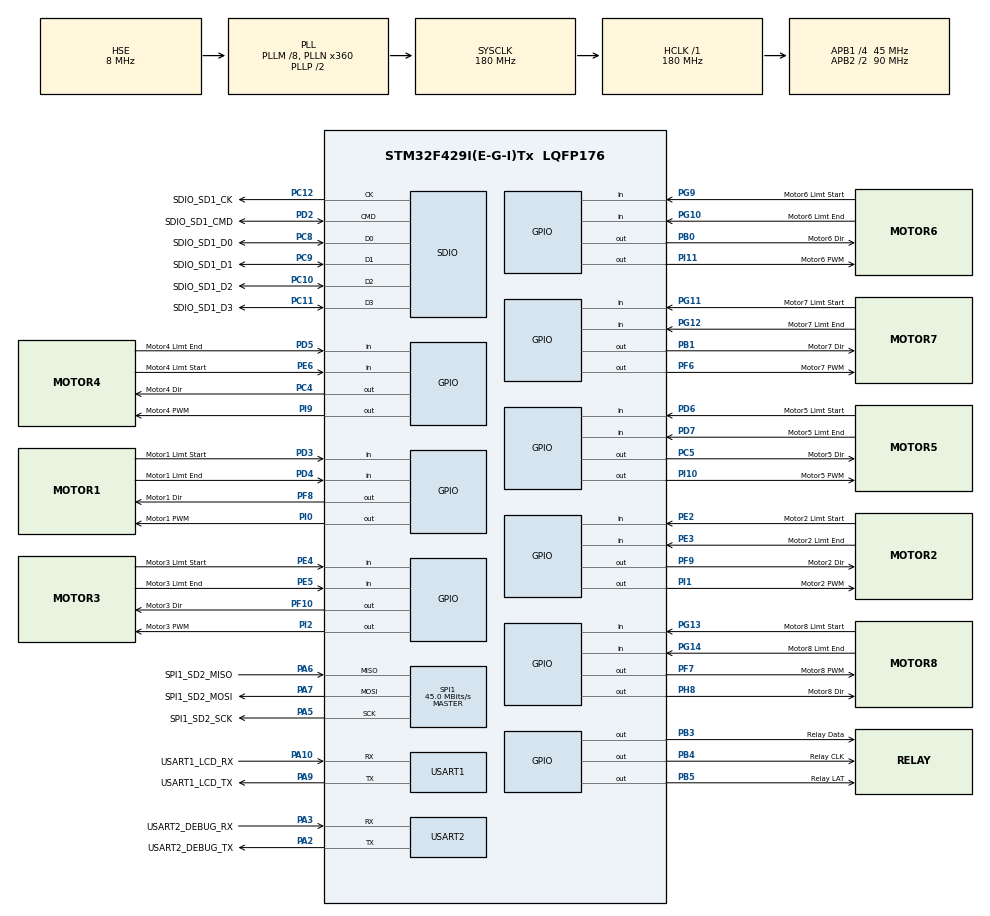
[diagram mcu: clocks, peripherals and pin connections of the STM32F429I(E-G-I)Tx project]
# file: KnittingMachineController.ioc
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Dma.Request0=SDIO_RX
Dma.Request1=SDIO_TX
Dma.SDIO_RX.0.Direction=DMA_PERIPH_TO_MEMORY
Dma.SDIO_RX.0.FIFOMode=DMA_FIFOMODE_ENABLE
Dma.SDIO_RX.0.FIFOThreshold=DMA_FIFO_THRESHOLD_FULL
Dma.SDIO_RX.0.Instance=DMA2_Stream3
Dma.SDIO_RX.0.MemBurst=DMA_MBURST_INC4
Dma.SDIO_RX.0.MemDataAlignment=DMA_MDATAALIGN_WORD
Dma.SDIO_RX.0.MemInc=DMA_MINC_ENABLE
Dma.SDIO_RX.0.Mode=DMA_PFCTRL
Dma.SDIO_RX.0.PeriphBurst=DMA_PBURST_INC4
Dma.SDIO_RX.0.PeriphDataAlignment=DMA_PDATAALIGN_WORD
Dma.SDIO_RX.0.PeriphInc=DMA_PINC_DISABLE
Dma.SDIO_RX.0.Priority=DMA_PRIORITY_LOW
Dma.SDIO_TX.1.Direction=DMA_MEMORY_TO_PERIPH
Dma.SDIO_TX.1.FIFOMode=DMA_FIFOMODE_ENABLE
Dma.SDIO_TX.1.FIFOThreshold=DMA_FIFO_THRESHOLD_FULL
Dma.SDIO_TX.1.Instance=DMA2_Stream6
Dma.SDIO_TX.1.MemBurst=DMA_MBURST_INC4
Dma.SDIO_TX.1.MemDataAlignment=DMA_MDATAALIGN_WORD
Dma.SDIO_TX.1.MemInc=DMA_MINC_ENABLE
Dma.SDIO_TX.1.Mode=DMA_PFCTRL
Dma.SDIO_TX.1.PeriphBurst=DMA_PBURST_INC4
Dma.SDIO_TX.1.PeriphDataAlignment=DMA_PDATAALIGN_WORD
Dma.SDIO_TX.1.PeriphInc=DMA_PINC_DISABLE
Dma.SDIO_TX.1.Priority=DMA_PRIORITY_LOW
Mcu.Family=STM32F4
Mcu.Name=STM32F429I(E-G-I)Tx
Mcu.Package=LQFP176
NVIC.DMA2_Stream3_IRQn=true\:6\:0\:true\:false\:true
NVIC.DMA2_Stream6_IRQn=true\:6\:0\:true\:false\:true
NVIC.PriorityGroup=NVIC_PRIORITYGROUP_4
NVIC.SDIO_IRQn=true\:5\:0\:true\:false\:true
NVIC.TIM1_UP_TIM10_IRQn=true\:0\:0\:false\:false\:true
NVIC.TIM2_IRQn=true\:0\:0\:false\:false\:true
NVIC.TIM3_IRQn=true\:0\:0\:false\:false\:true
NVIC.TIM4_IRQn=true\:0\:0\:false\:false\:true
NVIC.TIM5_IRQn=true\:0\:0\:false\:false\:true
NVIC.TIM6_DAC_IRQn=true\:0\:0\:true\:false\:true
NVIC.TIM7_IRQn=true\:0\:0\:true\:false\:true
NVIC.TIM8_UP_TIM13_IRQn=true\:0\:0\:false\:false\:true
NVIC.USART1_IRQn=true\:0\:0\:false\:false\:true
PA10.GPIO_Label=USART1_LCD_RX
PA10.Mode=Asynchronous
PA10.Signal=USART1_RX
PA13.Mode=Serial_Wire
PA13.Signal=SYS_JTMS-SWDIO
PA14.Mode=Serial_Wire
PA14.Signal=SYS_JTCK-SWCLK
PA2.GPIO_Label=USART2_DEBUG_TX
PA2.Mode=Asynchronous
PA2.Signal=USART2_TX
PA3.GPIO_Label=USART2_DEBUG_RX
PA3.Mode=Asynchronous
PA3.Signal=USART2_RX
PA5.GPIO_Label=SPI1_SD2_SCK
PA5.Mode=Full_Duplex_Master
PA5.Signal=SPI1_SCK
PA6.GPIO_Label=SPI1_SD2_MISO
PA6.Mode=Full_Duplex_Master
PA6.Signal=SPI1_MISO
PA7.GPIO_Label=SPI1_SD2_MOSI
PA7.Mode=Full_Duplex_Master
PA7.Signal=SPI1_MOSI
PA9.GPIO_Label=USART1_LCD_TX
PA9.Mode=Asynchronous
PA9.Signal=USART1_TX
PB0.GPIO_Label=Motor6 Dir
PB0.GPIO_Speed=GPIO_SPEED_FREQ_VERY_HIGH
PB0.Signal=GPIO_Output
PB1.GPIO_Label=Motor7 Dir
PB1.GPIO_Speed=GPIO_SPEED_FREQ_VERY_HIGH
PB1.Signal=GPIO_Output
PB3.GPIO_Label=Relay Data
PB3.GPIO_Speed=GPIO_SPEED_FREQ_VERY_HIGH
PB3.Signal=GPIO_Output
PB4.GPIO_Label=Relay CLK
PB4.GPIO_Speed=GPIO_SPEED_FREQ_VERY_HIGH
PB4.Signal=GPIO_Output
PB5.GPIO_Label=Relay LAT
PB5.GPIO_Speed=GPIO_SPEED_FREQ_VERY_HIGH
PB5.Signal=GPIO_Output
PC10.GPIO_Label=SDIO_SD1_D2
PC10.Mode=SD_4_bits_Wide_bus
PC10.Signal=SDIO_D2
PC11.GPIO_Label=SDIO_SD1_D3
PC11.Mode=SD_4_bits_Wide_bus
PC11.Signal=SDIO_D3
PC12.GPIO_Label=SDIO_SD1_CK
PC12.Mode=SD_4_bits_Wide_bus
PC12.Signal=SDIO_CK
PC4.GPIO_Label=Motor4 Dir
PC4.GPIO_Speed=GPIO_SPEED_FREQ_VERY_HIGH
PC4.Signal=GPIO_Output
PC5.GPIO_Label=Motor5 Dir
PC5.GPIO_Speed=GPIO_SPEED_FREQ_VERY_HIGH
PC5.Signal=GPIO_Output
PC8.GPIO_Label=SDIO_SD1_D0
PC8.Mode=SD_4_bits_Wide_bus
PC8.Signal=SDIO_D0
PC9.GPIO_Label=SDIO_SD1_D1
PC9.Mode=SD_4_bits_Wide_bus
PC9.Signal=SDIO_D1
PD2.GPIO_Label=SDIO_SD1_CMD
PD2.Mode=SD_4_bits_Wide_bus
PD2.Signal=SDIO_CMD
PD3.GPIO_Label=Motor1 Limt Start
PD3.GPIO_PuPd=GPIO_PULLUP
PD3.Signal=GPIO_Input
PD4.GPIO_Label=Motor1 Limt End
PD4.GPIO_PuPd=GPIO_PULLUP
PD4.Signal=GPIO_Input
PD5.GPIO_Label=Motor4 Limt End
PD5.GPIO_PuPd=GPIO_PULLUP
PD5.Signal=GPIO_Input
PD6.GPIO_Label=Motor5 Limt Start
PD6.GPIO_PuPd=GPIO_PULLUP
PD6.Signal=GPIO_Input
PD7.GPIO_Label=Motor5 Limt End
PD7.GPIO_PuPd=GPIO_PULLUP
PD7.Signal=GPIO_Input
PE2.GPIO_Label=Motor2 Limt Start
PE2.GPIO_PuPd=GPIO_PULLUP
PE2.Signal=GPIO_Input
PE3.GPIO_Label=Motor2 Limt End
PE3.GPIO_PuPd=GPIO_PULLUP
PE3.Signal=GPIO_Input
PE4.GPIO_Label=Motor3 Limt Start
PE4.GPIO_PuPd=GPIO_PULLUP
PE4.Signal=GPIO_Input
PE5.GPIO_Label=Motor3 Limt End
PE5.GPIO_PuPd=GPIO_PULLUP
PE5.Signal=GPIO_Input
PE6.GPIO_Label=Motor4 Limt Start
PE6.GPIO_PuPd=GPIO_PULLUP
PE6.Signal=GPIO_Input
PF10.GPIO_Label=Motor3 Dir
PF10.GPIO_Speed=GPIO_SPEED_FREQ_VERY_HIGH
PF10.Signal=GPIO_Output
PF6.GPIO_Label=Motor7 PWM
PF6.GPIO_Speed=GPIO_SPEED_FREQ_VERY_HIGH
PF6.Signal=GPIO_Output
PF7.GPIO_Label=Motor8 PWM
PF7.GPIO_Speed=GPIO_SPEED_FREQ_VERY_HIGH
PF7.Signal=GPIO_Output
PF8.GPIO_Label=Motor1 Dir
PF8.GPIO_Speed=GPIO_SPEED_FREQ_VERY_HIGH
PF8.Signal=GPIO_Output
PF9.GPIO_Label=Motor2 Dir
PF9.GPIO_Speed=GPIO_SPEED_FREQ_VERY_HIGH
PF9.Signal=GPIO_Output
PG10.GPIO_Label=Motor6 Limt End
PG10.GPIO_PuPd=GPIO_PULLUP
PG10.Signal=GPIO_Input
PG11.GPIO_Label=Motor7 Limt Start
PG11.GPIO_PuPd=GPIO_PULLUP
PG11.Signal=GPIO_Input
PG12.GPIO_Label=Motor7 Limt End
PG12.GPIO_PuPd=GPIO_PULLUP
PG12.Signal=GPIO_Input
PG13.GPIO_Label=Motor8 Limt Start
PG13.GPIO_PuPd=GPIO_PULLUP
PG13.Signal=GPIO_Input
PG14.GPIO_Label=Motor8 Limt End
PG14.GPIO_PuPd=GPIO_PULLUP
PG14.Signal=GPIO_Input
PG9.GPIO_Label=Motor6 Limt Start
PG9.GPIO_PuPd=GPIO_PULLUP
PG9.Signal=GPIO_Input
PH0/OSC_IN.Mode=HSE-External-Oscillator
PH0/OSC_IN.Signal=RCC_OSC_IN
PH1/OSC_OUT.Mode=HSE-External-Oscillator
PH1/OSC_OUT.Signal=RCC_OSC_OUT
PH8.GPIO_Label=Motor8 Dir
PH8.GPIO_Speed=GPIO_SPEED_FREQ_VERY_HIGH
PH8.Signal=GPIO_Output
PI0.GPIO_Label=Motor1 PWM
PI0.GPIO_Speed=GPIO_SPEED_FREQ_VERY_HIGH
PI0.Signal=GPIO_Output
PI1.GPIO_Label=Motor2 PWM
PI1.GPIO_Speed=GPIO_SPEED_FREQ_VERY_HIGH
PI1.Signal=GPIO_Output
PI10.GPIO_Label=Motor5 PWM
PI10.GPIO_Speed=GPIO_SPEED_FREQ_VERY_HIGH
PI10.Signal=GPIO_Output
PI11.GPIO_Label=Motor6 PWM
PI11.GPIO_Speed=GPIO_SPEED_FREQ_VERY_HIGH
PI11.Signal=GPIO_Output
PI2.GPIO_Label=Motor3 PWM
PI2.GPIO_Speed=GPIO_SPEED_FREQ_VERY_HIGH
PI2.Signal=GPIO_Output
PI9.GPIO_Label=Motor4 PWM
PI9.GPIO_Speed=GPIO_SPEED_FREQ_VERY_HIGH
PI9.Signal=GPIO_Output
ProjectManager.HeapSize=0x200
ProjectManager.StackSize=0x400
ProjectManager.TargetToolchain=MDK-ARM V5
RCC.48MHZClocksFreq_Value=45000000
RCC.AHBFreq_Value=180000000
RCC.APB1CLKDivider=RCC_HCLK_DIV4
RCC.APB1Freq_Value=45000000
RCC.APB1TimFreq_Value=90000000
RCC.APB2CLKDivider=RCC_HCLK_DIV2
RCC.APB2Freq_Value=90000000
RCC.APB2TimFreq_Value=180000000
RCC.CortexFreq_Value=22500000
RCC.Cortex_Div=SYSTICK_CLKSOURCE_HCLK_DIV8
RCC.HCLKFreq_Value=180000000
RCC.HSE_VALUE=8000000
RCC.HSI_VALUE=16000000
RCC.LSE_VALUE=32768
RCC.PLLM=8
RCC.PLLN=360
RCC.PLLQ=8
RCC.PLLSourceVirtual=RCC_PLLSOURCE_HSE
RCC.SYSCLKFreq_VALUE=180000000
RCC.SYSCLKSource=RCC_SYSCLKSOURCE_PLLCLK
RCC.VCOOutputFreq_Value=360000000
SDIO.BusWide=SDIO_BUS_WIDE_1B
SDIO.WideMode=SDIO_BUS_WIDE_4B
SPI1.BaudRatePrescaler=SPI_BAUDRATEPRESCALER_2
SPI1.CalculateBaudRate=45.0 MBits/s
SPI1.Mode=SPI_MODE_MASTER
TIM1.Period=1
TIM1.Prescaler=5000
TIM2.Period=1
TIM2.Prescaler=2500
TIM3.Period=1
TIM3.Prescaler=2500
TIM4.Period=1
TIM4.Prescaler=2500
TIM5.Period=1
TIM5.Prescaler=2500
TIM6.Period=1
TIM6.Prescaler=2500
TIM7.Period=1
TIM7.Prescaler=2500
TIM8.Period=1
TIM8.Prescaler=5000
VP_CRC_VS_CRC.Mode=CRC_Activate
VP_TIM1_VS_ClockSourceINT.Mode=Internal
VP_TIM2_VS_ClockSourceINT.Mode=Internal
VP_TIM3_VS_ClockSourceINT.Mode=Internal
VP_TIM4_VS_ClockSourceINT.Mode=Internal
VP_TIM5_VS_ClockSourceINT.Mode=Internal
VP_TIM6_VS_ClockSourceINT.Mode=Enable_Timer
VP_TIM7_VS_ClockSourceINT.Mode=Enable_Timer
VP_TIM8_VS_ClockSourceINT.Mode=Internal
board=KnittingMachineController

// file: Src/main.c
/**
  ******************************************************************************
  * File Name          : main.c
  * Description        : Main program body
  ******************************************************************************
  *
  * COPYRIGHT(c) 2016 STMicroelectronics
  *
  * Redistribution and use in source and binary forms, with or without modification,
  * are permitted provided that the following conditions are met:
  *   1. Redistributions of source code must retain the above copyright notice,
  *      this list of conditions and the following disclaimer.
  *   2. Redistributions in binary form must reproduce the above copyright notice,
  *      this list of conditions and the following disclaimer in the documentation
  *      and/or other materials provided with the distribution.
  *   3. Neither the name of STMicroelectronics nor the names of its contributors
  *      may be used to endorse or promote products derived from this software
  *      without specific prior written permission.
  *
  * THIS SOFTWARE IS PROVIDED BY THE COPYRIGHT HOLDERS AND CONTRIBUTORS "AS IS"
  * AND ANY EXPRESS OR IMPLIED WARRANTIES, INCLUDING, BUT NOT LIMITED TO, THE
  * IMPLIED WARRANTIES OF MERCHANTABILITY AND FITNESS FOR A PARTICULAR PURPOSE ARE
  * DISCLAIMED. IN NO EVENT SHALL THE COPYRIGHT HOLDER OR CONTRIBUTORS BE LIABLE
  * FOR ANY DIRECT, INDIRECT, INCIDENTAL, SPECIAL, EXEMPLARY, OR CONSEQUENTIAL
  * DAMAGES (INCLUDING, BUT NOT LIMITED TO, PROCUREMENT OF SUBSTITUTE GOODS OR
  * SERVICES; LOSS OF USE, DATA, OR PROFITS; OR BUSINESS INTERRUPTION) HOWEVER
  * CAUSED AND ON ANY THEORY OF LIABILITY, WHETHER IN CONTRACT, STRICT LIABILITY,
  * OR TORT (INCLUDING NEGLIGENCE OR OTHERWISE) ARISING IN ANY WAY OUT OF THE USE
  * OF THIS SOFTWARE, EVEN IF ADVISED OF THE POSSIBILITY OF SUCH DAMAGE.
  *
  ******************************************************************************
  */
#include "stm32f4xx_hal.h"

/* USER CODE BEGIN Includes */
#include <string.h>
/* USER CODE END Includes */

CRC_HandleTypeDef hcrc;

SD_HandleTypeDef hsd;
HAL_SD_CardInfoTypedef SDCardInfo;
DMA_HandleTypeDef hdma_sdio_rx;
DMA_HandleTypeDef hdma_sdio_tx;

SPI_HandleTypeDef hspi1;

TIM_HandleTypeDef htim1;
TIM_HandleTypeDef htim2;
TIM_HandleTypeDef htim3;
TIM_HandleTypeDef htim4;
TIM_HandleTypeDef htim5;
TIM_HandleTypeDef htim6;
TIM_HandleTypeDef htim7;
TIM_HandleTypeDef htim8;

UART_HandleTypeDef huart1;
UART_HandleTypeDef huart2;

/* USER CODE BEGIN PV */
/* Private variables ---------------------------------------------------------*/
HAL_SD_ErrorTypedef Status;
uint32_t Buffer_Tx[512/4], Buffer_Rx[512/4];
uint32_t i;
/* Buffer used for reception */
uint8_t aRxBuffer[20];
/* USER CODE END PV */

void SystemClock_Config(void);
void Error_Handler(void);
static void MX_GPIO_Init(void);
static void MX_DMA_Init(void);
static void MX_CRC_Init(void);
static void MX_SDIO_SD_Init(void);
static void MX_SPI1_Init(void);
static void MX_TIM1_Init(void);
static void MX_TIM2_Init(void);
static void MX_TIM3_Init(void);
static void MX_TIM4_Init(void);
static void MX_TIM5_Init(void);
static void MX_TIM6_Init(void);
static void MX_TIM7_Init(void);
static void MX_TIM8_Init(void);
static void MX_USART1_UART_Init(void);
static void MX_USART2_UART_Init(void);

/* USER CODE BEGIN PFP */
/* Private function prototypes -----------------------------------------------*/

/* USER CODE END PFP */

/* USER CODE BEGIN 0 */
	//define printf function for UART2
	#ifdef __GNUC__
		/* With GCC/RAISONANCE, small printf (option LD Linker->Libraries->Small printf
			 set to 'Yes') calls __io_putchar() */
		#define PUTCHAR_PROTOTYPE int __io_putchar(int ch)
	#else
		#define PUTCHAR_PROTOTYPE int fputc(int ch, FILE *f)
	#endif /* __GNUC__ */
	/**
		* @brief  Retargets the C library printf function to the USART.
		* @param  None
		* @retval None
		*/
	PUTCHAR_PROTOTYPE
	{
		/* Place your implementation of fputc here */
		/* e.g. write a character to the EVAL_COM1 and Loop until the end of transmission */
		HAL_UART_Transmit(&huart2, (uint8_t *)&ch, 1, 0xFFFF);

		return ch;
	}
/* USER CODE END 0 */

int main(void)
{

  /* MCU Configuration----------------------------------------------------------*/

  /* Reset of all peripherals, Initializes the Flash interface and the Systick. */
  HAL_Init();

  /* Configure the system clock */
  SystemClock_Config();

  /* Initialize all configured peripherals */
  MX_GPIO_Init();
  MX_DMA_Init();
  MX_CRC_Init();
  MX_SDIO_SD_Init();
  MX_SPI1_Init();
  MX_TIM1_Init();
  MX_TIM2_Init();
  MX_TIM3_Init();
  MX_TIM4_Init();
  MX_TIM5_Init();
  MX_TIM6_Init();
  MX_TIM7_Init();
  MX_TIM8_Init();
  MX_USART1_UART_Init();
  MX_USART2_UART_Init();

  /* USER CODE BEGIN 2 */
	HAL_TIM_Base_Start_IT(&htim1);
	HAL_Delay(10);
	HAL_TIM_Base_Start_IT(&htim2);
	HAL_Delay(10);
	HAL_TIM_Base_Start_IT(&htim3);
	HAL_Delay(10);
	HAL_TIM_Base_Start_IT(&htim4);
	HAL_Delay(10);
	HAL_TIM_Base_Start_IT(&htim5);
	HAL_Delay(10);
	HAL_TIM_Base_Start_IT(&htim6);
	HAL_Delay(10);
	HAL_TIM_Base_Start_IT(&htim7);
	HAL_Delay(10);
	HAL_TIM_Base_Start_IT(&htim8);
	HAL_Delay(10);
	HAL_UART_Receive_IT(&huart1, (uint8_t *)aRxBuffer, 10);

	//SD testing
		printf(" Warning: this program may erase all the TF card data. \r\n");

    printf("\r\n Initialize SD card successfully!\r\n\r\n");
    printf(" SD card information! \r\n");
    printf(" CardCapacity  : %llu \r\n",SDCardInfo.CardCapacity );
    printf(" CardBlockSize : %d \r\n",SDCardInfo.CardBlockSize);
    printf(" RCA           : %d \r\n",SDCardInfo.RCA);
    printf(" CardType      : %d \r\n",SDCardInfo.CardType);

    /*------------------- Block Write --------------------------*/
    memset(Buffer_Tx,0x15,sizeof(Buffer_Tx));
    if(HAL_SD_WriteBlocks_DMA(&hsd, Buffer_Tx, 0, 512, 1) == SD_OK)
    {
        Status = HAL_SD_CheckWriteOperation(&hsd, (uint32_t)100000000);
        if (Status == SD_OK)
        {
            printf("\r\n Write block successfully!\r\n");
            for(i=0;i<sizeof(Buffer_Tx)>>2;i++)
            {
                printf("%02x:0x%08x ",i,Buffer_Tx[i]);
            }
            printf("\r\n");
        }
        else
            printf("\r\n Write block fail!\r\n");
    }

    /*------------------- Block Read --------------------------*/
    if(HAL_SD_ReadBlocks_DMA(&hsd, Buffer_Rx, 0, 512, 1) == SD_OK)
    {
        Status = HAL_SD_CheckReadOperation(&hsd, 0xFFFF);
        if (Status == SD_OK)
        {
            printf("\r\n Read block successfully!\r\n");
            for(i=0;i<sizeof(Buffer_Rx)>>2;i++)
            {
                printf("%02x:0x%08x ",i,Buffer_Rx[i]);
            }
            printf("\r\n");
        }
        else
            printf("\r\n Read block fail!\r\n");
    }

    /*------------------- Block Erase -------------------------------*/
    Status = HAL_SD_Erase(&hsd, 0, 512);
    if (Status == SD_OK)
			printf("\r\n Erase block successfully!\r\n");
    else
        printf("\r\n Erase block fail!\r\n");

    /*------------------- Block Read --------------------------*/
    if(HAL_SD_ReadBlocks_DMA(&hsd, Buffer_Rx, 0, 512, 1) == SD_OK)
    {
        Status = HAL_SD_CheckReadOperation(&hsd, 0xFFFF);
        if (Status == SD_OK)
        {
            printf("\r\n Read block successfully!\r\n");
            for(i=0;i<sizeof(Buffer_Rx)>>2;i++)
            {
                printf("%02x:0x%08x ",i,Buffer_Rx[i]);
            }
            printf("\r\n");
        }
        else
            printf("\r\n Read block fail!\r\n");
    }
  /* USER CODE END 2 */

  /* Infinite loop */
  /* USER CODE BEGIN WHILE */
	//HAL_UART_Transmit_IT(&huart1, uart_trans, 2);
	//HAL_UART_Transmit(&huart2, uart_trans, 2, 1000);
	printf("\nwelcome to www.waveshere.com !!!\n");
  while (1)
  {
  /* USER CODE END WHILE */

  /* USER CODE BEGIN 3 */

		//HAL_UART_Transmit_IT(&huart1, uart_trans, 2);
		//HAL_GPIO_TogglePin(GPIOF, Motor8_PWM_Pin);
  }
  /* USER CODE END 3 */

}

/** System Clock Configuration
*/
void SystemClock_Config(void)
{

  RCC_OscInitTypeDef RCC_OscInitStruct;
  RCC_ClkInitTypeDef RCC_ClkInitStruct;

  __HAL_RCC_PWR_CLK_ENABLE();

  __HAL_PWR_VOLTAGESCALING_CONFIG(PWR_REGULATOR_VOLTAGE_SCALE1);

  RCC_OscInitStruct.OscillatorType = RCC_OSCILLATORTYPE_HSE;
  RCC_OscInitStruct.HSEState = RCC_HSE_ON;
  RCC_OscInitStruct.PLL.PLLState = RCC_PLL_ON;
  RCC_OscInitStruct.PLL.PLLSource = RCC_PLLSOURCE_HSE;
  RCC_OscInitStruct.PLL.PLLM = 8;
  RCC_OscInitStruct.PLL.PLLN = 360;
  RCC_OscInitStruct.PLL.PLLP = RCC_PLLP_DIV2;
  RCC_OscInitStruct.PLL.PLLQ = 8;
  if (HAL_RCC_OscConfig(&RCC_OscInitStruct) != HAL_OK)
  {
    Error_Handler();
  }

  if (HAL_PWREx_EnableOverDrive() != HAL_OK)
  {
    Error_Handler();
  }

  RCC_ClkInitStruct.ClockType = RCC_CLOCKTYPE_HCLK|RCC_CLOCKTYPE_SYSCLK
                              |RCC_CLOCKTYPE_PCLK1|RCC_CLOCKTYPE_PCLK2;
  RCC_ClkInitStruct.SYSCLKSource = RCC_SYSCLKSOURCE_PLLCLK;
  RCC_ClkInitStruct.AHBCLKDivider = RCC_SYSCLK_DIV1;
  RCC_ClkInitStruct.APB1CLKDivider = RCC_HCLK_DIV4;
  RCC_ClkInitStruct.APB2CLKDivider = RCC_HCLK_DIV2;
  if (HAL_RCC_ClockConfig(&RCC_ClkInitStruct, FLASH_LATENCY_5) != HAL_OK)
  {
    Error_Handler();
  }

  HAL_SYSTICK_Config(HAL_RCC_GetHCLKFreq()/8000);

  HAL_SYSTICK_CLKSourceConfig(SYSTICK_CLKSOURCE_HCLK_DIV8);

  /* SysTick_IRQn interrupt configuration */
  HAL_NVIC_SetPriority(SysTick_IRQn, 0, 0);
}

/* CRC init function */
static void MX_CRC_Init(void)
{

  hcrc.Instance = CRC;
  if (HAL_CRC_Init(&hcrc) != HAL_OK)
  {
    Error_Handler();
  }

}

/* SDIO init function */
static void MX_SDIO_SD_Init(void)
{

  hsd.Instance = SDIO;
  hsd.Init.ClockEdge = SDIO_CLOCK_EDGE_RISING;
  hsd.Init.ClockBypass = SDIO_CLOCK_BYPASS_DISABLE;
  hsd.Init.ClockPowerSave = SDIO_CLOCK_POWER_SAVE_DISABLE;
  hsd.Init.BusWide = SDIO_BUS_WIDE_1B;
  hsd.Init.HardwareFlowControl = SDIO_HARDWARE_FLOW_CONTROL_DISABLE;
  hsd.Init.ClockDiv = 0;
  if (HAL_SD_Init(&hsd, &SDCardInfo) != SD_OK)
  {
    Error_Handler();
  }

  HAL_SD_WideBusOperation_Config(&hsd, SDIO_BUS_WIDE_4B);

}

/* SPI1 init function */
static void MX_SPI1_Init(void)
{

  hspi1.Instance = SPI1;
  hspi1.Init.Mode = SPI_MODE_MASTER;
  hspi1.Init.Direction = SPI_DIRECTION_2LINES;
  hspi1.Init.DataSize = SPI_DATASIZE_8BIT;
  hspi1.Init.CLKPolarity = SPI_POLARITY_LOW;
  hspi1.Init.CLKPhase = SPI_PHASE_1EDGE;
  hspi1.Init.NSS = SPI_NSS_SOFT;
  hspi1.Init.BaudRatePrescaler = SPI_BAUDRATEPRESCALER_2;
  hspi1.Init.FirstBit = SPI_FIRSTBIT_MSB;
  hspi1.Init.TIMode = SPI_TIMODE_DISABLE;
  hspi1.Init.CRCCalculation = SPI_CRCCALCULATION_DISABLE;
  hspi1.Init.CRCPolynomial = 10;
  if (HAL_SPI_Init(&hspi1) != HAL_OK)
  {
    Error_Handler();
  }

}

/* TIM1 init function */
static void MX_TIM1_Init(void)
{

  TIM_ClockConfigTypeDef sClockSourceConfig;
  TIM_MasterConfigTypeDef sMasterConfig;

  htim1.Instance = TIM1;
  htim1.Init.Prescaler = 5000;
  htim1.Init.CounterMode = TIM_COUNTERMODE_UP;
  htim1.Init.Period = 1;
  htim1.Init.ClockDivision = TIM_CLOCKDIVISION_DIV1;
  htim1.Init.RepetitionCounter = 0;
  if (HAL_TIM_Base_Init(&htim1) != HAL_OK)
  {
    Error_Handler();
  }

  sClockSourceConfig.ClockSource = TIM_CLOCKSOURCE_INTERNAL;
  if (HAL_TIM_ConfigClockSource(&htim1, &sClockSourceConfig) != HAL_OK)
  {
    Error_Handler();
  }

  sMasterConfig.MasterOutputTrigger = TIM_TRGO_RESET;
  sMasterConfig.MasterSlaveMode = TIM_MASTERSLAVEMODE_DISABLE;
  if (HAL_TIMEx_MasterConfigSynchronization(&htim1, &sMasterConfig) != HAL_OK)
  {
    Error_Handler();
  }

}

/* TIM2 init function */
static void MX_TIM2_Init(void)
{

  TIM_ClockConfigTypeDef sClockSourceConfig;
  TIM_MasterConfigTypeDef sMasterConfig;

  htim2.Instance = TIM2;
  htim2.Init.Prescaler = 2500;
  htim2.Init.CounterMode = TIM_COUNTERMODE_UP;
  htim2.Init.Period = 1;
  htim2.Init.ClockDivision = TIM_CLOCKDIVISION_DIV1;
  if (HAL_TIM_Base_Init(&htim2) != HAL_OK)
  {
    Error_Handler();
  }

  sClockSourceConfig.ClockSource = TIM_CLOCKSOURCE_INTERNAL;
  if (HAL_TIM_ConfigClockSource(&htim2, &sClockSourceConfig) != HAL_OK)
  {
    Error_Handler();
  }

  sMasterConfig.MasterOutputTrigger = TIM_TRGO_RESET;
  sMasterConfig.MasterSlaveMode = TIM_MASTERSLAVEMODE_DISABLE;
  if (HAL_TIMEx_MasterConfigSynchronization(&htim2, &sMasterConfig) != HAL_OK)
  {
    Error_Handler();
  }

}

/* TIM3 init function */
static void MX_TIM3_Init(void)
{

  TIM_ClockConfigTypeDef sClockSourceConfig;
  TIM_MasterConfigTypeDef sMasterConfig;

  htim3.Instance = TIM3;
  htim3.Init.Prescaler = 2500;
  htim3.Init.CounterMode = TIM_COUNTERMODE_UP;
  htim3.Init.Period = 1;
  htim3.Init.ClockDivision = TIM_CLOCKDIVISION_DIV1;
  if (HAL_TIM_Base_Init(&htim3) != HAL_OK)
  {
    Error_Handler();
  }

  sClockSourceConfig.ClockSource = TIM_CLOCKSOURCE_INTERNAL;
  if (HAL_TIM_ConfigClockSource(&htim3, &sClockSourceConfig) != HAL_OK)
  {
    Error_Handler();
  }

  sMasterConfig.MasterOutputTrigger = TIM_TRGO_RESET;
  sMasterConfig.MasterSlaveMode = TIM_MASTERSLAVEMODE_DISABLE;
  if (HAL_TIMEx_MasterConfigSynchronization(&htim3, &sMasterConfig) != HAL_OK)
  {
    Error_Handler();
  }

}

/* TIM4 init function */
static void MX_TIM4_Init(void)
{

  TIM_ClockConfigTypeDef sClockSourceConfig;
  TIM_MasterConfigTypeDef sMasterConfig;

  htim4.Instance = TIM4;
  htim4.Init.Prescaler = 2500;
  htim4.Init.CounterMode = TIM_COUNTERMODE_UP;
  htim4.Init.Period = 1;
  htim4.Init.ClockDivision = TIM_CLOCKDIVISION_DIV1;
  if (HAL_TIM_Base_Init(&htim4) != HAL_OK)
  {
    Error_Handler();
  }

  sClockSourceConfig.ClockSource = TIM_CLOCKSOURCE_INTERNAL;
  if (HAL_TIM_ConfigClockSource(&htim4, &sClockSourceConfig) != HAL_OK)
  {
    Error_Handler();
  }

  sMasterConfig.MasterOutputTrigger = TIM_TRGO_RESET;
  sMasterConfig.MasterSlaveMode = TIM_MASTERSLAVEMODE_DISABLE;
  if (HAL_TIMEx_MasterConfigSynchronization(&htim4, &sMasterConfig) != HAL_OK)
  {
    Error_Handler();
  }

}

/* TIM5 init function */
static void MX_TIM5_Init(void)
{

  TIM_ClockConfigTypeDef sClockSourceConfig;
  TIM_MasterConfigTypeDef sMasterConfig;

  htim5.Instance = TIM5;
  htim5.Init.Prescaler = 2500;
  htim5.Init.CounterMode = TIM_COUNTERMODE_UP;
  htim5.Init.Period = 1;
  htim5.Init.ClockDivision = TIM_CLOCKDIVISION_DIV1;
  if (HAL_TIM_Base_Init(&htim5) != HAL_OK)
  {
    Error_Handler();
  }

  sClockSourceConfig.ClockSource = TIM_CLOCKSOURCE_INTERNAL;
  if (HAL_TIM_ConfigClockSource(&htim5, &sClockSourceConfig) != HAL_OK)
  {
    Error_Handler();
  }

  sMasterConfig.MasterOutputTrigger = TIM_TRGO_RESET;
  sMasterConfig.MasterSlaveMode = TIM_MASTERSLAVEMODE_DISABLE;
  if (HAL_TIMEx_MasterConfigSynchronization(&htim5, &sMasterConfig) != HAL_OK)
  {
    Error_Handler();
  }

}

/* TIM6 init function */
static void MX_TIM6_Init(void)
{

  TIM_MasterConfigTypeDef sMasterConfig;

  htim6.Instance = TIM6;
  htim6.Init.Prescaler = 2500;
  htim6.Init.CounterMode = TIM_COUNTERMODE_UP;
  htim6.Init.Period = 1;
  if (HAL_TIM_Base_Init(&htim6) != HAL_OK)
  {
    Error_Handler();
  }

  sMasterConfig.MasterOutputTrigger = TIM_TRGO_RESET;
  sMasterConfig.MasterSlaveMode = TIM_MASTERSLAVEMODE_DISABLE;
  if (HAL_TIMEx_MasterConfigSynchronization(&htim6, &sMasterConfig) != HAL_OK)
  {
    Error_Handler();
  }

}

/* TIM7 init function */
static void MX_TIM7_Init(void)
{

  TIM_MasterConfigTypeDef sMasterConfig;

  htim7.Instance = TIM7;
  htim7.Init.Prescaler = 2500;
  htim7.Init.CounterMode = TIM_COUNTERMODE_UP;
  htim7.Init.Period = 1;
  if (HAL_TIM_Base_Init(&htim7) != HAL_OK)
  {
    Error_Handler();
  }

  sMasterConfig.MasterOutputTrigger = TIM_TRGO_RESET;
  sMasterConfig.MasterSlaveMode = TIM_MASTERSLAVEMODE_DISABLE;
  if (HAL_TIMEx_MasterConfigSynchronization(&htim7, &sMasterConfig) != HAL_OK)
  {
    Error_Handler();
  }

}

/* TIM8 init function */
static void MX_TIM8_Init(void)
{

  TIM_ClockConfigTypeDef sClockSourceConfig;
  TIM_MasterConfigTypeDef sMasterConfig;

  htim8.Instance = TIM8;
  htim8.Init.Prescaler = 5000;
  htim8.Init.CounterMode = TIM_COUNTERMODE_UP;
  htim8.Init.Period = 1;
  htim8.Init.ClockDivision = TIM_CLOCKDIVISION_DIV1;
  htim8.Init.RepetitionCounter = 0;
  if (HAL_TIM_Base_Init(&htim8) != HAL_OK)
  {
    Error_Handler();
  }

  sClockSourceConfig.ClockSource = TIM_CLOCKSOURCE_INTERNAL;
  if (HAL_TIM_ConfigClockSource(&htim8, &sClockSourceConfig) != HAL_OK)
  {
    Error_Handler();
  }

  sMasterConfig.MasterOutputTrigger = TIM_TRGO_RESET;
  sMasterConfig.MasterSlaveMode = TIM_MASTERSLAVEMODE_DISABLE;
  if (HAL_TIMEx_MasterConfigSynchronization(&htim8, &sMasterConfig) != HAL_OK)
  {
    Error_Handler();
  }

}

/* USART1 init function */
static void MX_USART1_UART_Init(void)
{

  huart1.Instance = USART1;
  huart1.Init.BaudRate = 115200;
  huart1.Init.WordLength = UART_WORDLENGTH_8B;
  huart1.Init.StopBits = UART_STOPBITS_1;
  huart1.Init.Parity = UART_PARITY_NONE;
  huart1.Init.Mode = UART_MODE_TX_RX;
  huart1.Init.HwFlowCtl = UART_HWCONTROL_NONE;
  huart1.Init.OverSampling = UART_OVERSAMPLING_16;
  if (HAL_UART_Init(&huart1) != HAL_OK)
  {
    Error_Handler();
  }

}

/* USART2 init function */
static void MX_USART2_UART_Init(void)
{

  huart2.Instance = USART2;
  huart2.Init.BaudRate = 115200;
  huart2.Init.WordLength = UART_WORDLENGTH_8B;
  huart2.Init.StopBits = UART_STOPBITS_1;
  huart2.Init.Parity = UART_PARITY_NONE;
  huart2.Init.Mode = UART_MODE_TX_RX;
  huart2.Init.HwFlowCtl = UART_HWCONTROL_NONE;
  huart2.Init.OverSampling = UART_OVERSAMPLING_16;
  if (HAL_UART_Init(&huart2) != HAL_OK)
  {
    Error_Handler();
  }

}

static void MX_DMA_Init(void)
{
  /* DMA controller clock enable */
  __HAL_RCC_DMA2_CLK_ENABLE();

  /* DMA interrupt init */
  /* DMA2_Stream3_IRQn interrupt configuration */
  HAL_NVIC_SetPriority(DMA2_Stream3_IRQn, 6, 0);
  HAL_NVIC_EnableIRQ(DMA2_Stream3_IRQn);
  /* DMA2_Stream6_IRQn interrupt configuration */
  HAL_NVIC_SetPriority(DMA2_Stream6_IRQn, 6, 0);
  HAL_NVIC_EnableIRQ(DMA2_Stream6_IRQn);

}

/** Configure pins as
        * Analog
        * Input
        * Output
        * EVENT_OUT
        * EXTI
*/
static void MX_GPIO_Init(void)
{

  GPIO_InitTypeDef GPIO_InitStruct;

  /* GPIO Ports Clock Enable */
  __HAL_RCC_GPIOE_CLK_ENABLE();
  __HAL_RCC_GPIOI_CLK_ENABLE();
  __HAL_RCC_GPIOF_CLK_ENABLE();
  __HAL_RCC_GPIOH_CLK_ENABLE();
  __HAL_RCC_GPIOA_CLK_ENABLE();
  __HAL_RCC_GPIOC_CLK_ENABLE();
  __HAL_RCC_GPIOD_CLK_ENABLE();
  __HAL_RCC_GPIOG_CLK_ENABLE();
  __HAL_RCC_GPIOB_CLK_ENABLE();

  /*Configure GPIO pins : Motor2_Limt_Start_Pin Motor2_Limt_End_Pin Motor3_Limt_Start_Pin Motor3_Limt_End_Pin
                           Motor4_Limt_Start_Pin Motor4_Limt_End_Pin Motor5_Limt_Start_Pin Motor5_Limt_End_Pin
                           Motor6_Limt_Start_Pin Motor6_Limt_End_Pin Motor7_Limt_Start_Pin Motor7_Limt_End_Pin
                           Motor8_Limt_Start_Pin Motor8_Limt_End_Pin Motor1_Limt_Start_Pin Motor1_Limt_End_Pin */
  GPIO_InitStruct.Pin = Motor2_Limt_Start_Pin|Motor2_Limt_End_Pin|Motor3_Limt_Start_Pin|Motor3_Limt_End_Pin
                          |Motor4_Limt_Start_Pin|Motor4_Limt_End_Pin|Motor5_Limt_Start_Pin|Motor5_Limt_End_Pin
                          |Motor6_Limt_Start_Pin|Motor6_Limt_End_Pin|Motor7_Limt_Start_Pin|Motor7_Limt_End_Pin
                          |Motor8_Limt_Start_Pin|Motor8_Limt_End_Pin|Motor1_Limt_Start_Pin|Motor1_Limt_End_Pin;
  GPIO_InitStruct.Mode = GPIO_MODE_INPUT;
  GPIO_InitStruct.Pull = GPIO_PULLUP;
  HAL_GPIO_Init(GPIOE, &GPIO_InitStruct);

  /*Configure GPIO pin : PI8 */
  GPIO_InitStruct.Pin = GPIO_PIN_8;
  GPIO_InitStruct.Mode = GPIO_MODE_OUTPUT_PP;
  GPIO_InitStruct.Pull = GPIO_NOPULL;
  GPIO_InitStruct.Speed = GPIO_SPEED_FREQ_LOW;
  HAL_GPIO_Init(GPIOI, &GPIO_InitStruct);

  /*Configure GPIO pins : PI9 PI10 PI11 PI0
                           PI1 PI2 PI3 PI4
                           PI5 PI6 PI7 */
  GPIO_InitStruct.Pin = GPIO_PIN_9|GPIO_PIN_10|GPIO_PIN_11|GPIO_PIN_0
                          |GPIO_PIN_1|GPIO_PIN_2|GPIO_PIN_3|GPIO_PIN_4
                          |GPIO_PIN_5|GPIO_PIN_6|GPIO_PIN_7;
  GPIO_InitStruct.Mode = GPIO_MODE_OUTPUT_PP;
  GPIO_InitStruct.Pull = GPIO_NOPULL;
  GPIO_InitStruct.Speed = GPIO_SPEED_FREQ_VERY_HIGH;
  HAL_GPIO_Init(GPIOI, &GPIO_InitStruct);

  /*Configure GPIO pins : Motor1_PWM_Pin Motor2_PWM_Pin Motor3_PWM_Pin Motor4_PWM_Pin
                           Motor5_PWM_Pin Motor6_PWM_Pin Motor7_PWM_Pin Motor8_PWM_Pin
                           Motor1_Dir_Pin Motor2_Dir_Pin Motor3_Dir_Pin Motor4_Dir_Pin
                           Motor5_Dir_Pin Motor6_Dir_Pin Motor7_Dir_Pin Motor8_Dir_Pin */
  GPIO_InitStruct.Pin = Motor1_PWM_Pin|Motor2_PWM_Pin|Motor3_PWM_Pin|Motor4_PWM_Pin
                          |Motor5_PWM_Pin|Motor6_PWM_Pin|Motor7_PWM_Pin|Motor8_PWM_Pin
                          |Motor1_Dir_Pin|Motor2_Dir_Pin|Motor3_Dir_Pin|Motor4_Dir_Pin
                          |Motor5_Dir_Pin|Motor6_Dir_Pin|Motor7_Dir_Pin|Motor8_Dir_Pin;
  GPIO_InitStruct.Mode = GPIO_MODE_OUTPUT_PP;
  GPIO_InitStruct.Pull = GPIO_NOPULL;
  GPIO_InitStruct.Speed = GPIO_SPEED_FREQ_VERY_HIGH;
  HAL_GPIO_Init(GPIOF, &GPIO_InitStruct);

  /*Configure GPIO pins : PD6 PD7 */
  GPIO_InitStruct.Pin = GPIO_PIN_6|GPIO_PIN_7;
  GPIO_InitStruct.Mode = GPIO_MODE_INPUT;
  GPIO_InitStruct.Pull = GPIO_PULLUP;
  HAL_GPIO_Init(GPIOD, &GPIO_InitStruct);

  /*Configure GPIO pins : PG9 PG10 PG11 PG12
                           PG13 PG14 */
  GPIO_InitStruct.Pin = GPIO_PIN_9|GPIO_PIN_10|GPIO_PIN_11|GPIO_PIN_12
                          |GPIO_PIN_13|GPIO_PIN_14;
  GPIO_InitStruct.Mode = GPIO_MODE_INPUT;
  GPIO_InitStruct.Pull = GPIO_PULLUP;
  HAL_GPIO_Init(GPIOG, &GPIO_InitStruct);

  /*Configure GPIO pins : Relay_Data_Pin Relay_CLK_Pin Relay_LAT_Pin */
  GPIO_InitStruct.Pin = Relay_Data_Pin|Relay_CLK_Pin|Relay_LAT_Pin;
  GPIO_InitStruct.Mode = GPIO_MODE_OUTPUT_PP;
  GPIO_InitStruct.Pull = GPIO_NOPULL;
  GPIO_InitStruct.Speed = GPIO_SPEED_FREQ_VERY_HIGH;
  HAL_GPIO_Init(GPIOB, &GPIO_InitStruct);

  /*Configure GPIO pin Output Level */
  HAL_GPIO_WritePin(GPIOI, GPIO_PIN_8|GPIO_PIN_9|GPIO_PIN_10|GPIO_PIN_11
                          |GPIO_PIN_0|GPIO_PIN_1|GPIO_PIN_2|GPIO_PIN_3
                          |GPIO_PIN_4|GPIO_PIN_5|GPIO_PIN_6|GPIO_PIN_7, GPIO_PIN_RESET);

  /*Configure GPIO pin Output Level */
  HAL_GPIO_WritePin(GPIOF, Motor1_PWM_Pin|Motor2_PWM_Pin|Motor3_PWM_Pin|Motor4_PWM_Pin
                          |Motor5_PWM_Pin|Motor6_PWM_Pin|Motor7_PWM_Pin|Motor8_PWM_Pin
                          |Motor1_Dir_Pin|Motor2_Dir_Pin|Motor3_Dir_Pin|Motor4_Dir_Pin
                          |Motor5_Dir_Pin|Motor6_Dir_Pin|Motor7_Dir_Pin|Motor8_Dir_Pin, GPIO_PIN_RESET);

  /*Configure GPIO pin Output Level */
  HAL_GPIO_WritePin(GPIOB, Relay_Data_Pin|Relay_CLK_Pin|Relay_LAT_Pin, GPIO_PIN_RESET);

}

/* USER CODE BEGIN 4 */
/**
  * @brief Rx Transfer completed callbacks
  * @param huart: uart handle
  * @retval None
  */
void HAL_UART_RxCpltCallback(UART_HandleTypeDef *huart)
{
    HAL_UART_Receive_IT(&huart1, (uint8_t *)aRxBuffer, 10);
    HAL_UART_Transmit(&huart1, (uint8_t *)aRxBuffer, 10,0xFFFF);
}

/**
  * @brief  Period elapsed callback in non blocking mode
  * @param  htim: TIM handle
  * @retval None
  */
void HAL_TIM_PeriodElapsedCallback(TIM_HandleTypeDef *htim)
{
    if (htim->Instance == htim1.Instance)
    {
        /* Toggle LED */
        HAL_GPIO_TogglePin(GPIOF, Motor1_PWM_Pin);
    }
		else if (htim->Instance == htim2.Instance)
    {
        /* Toggle LED */
        HAL_GPIO_TogglePin(GPIOF, Motor2_PWM_Pin);
    }
		else if (htim->Instance == htim3.Instance)
    {
        /* Toggle LED */
        HAL_GPIO_TogglePin(GPIOF, Motor3_PWM_Pin);
    }
		else if (htim->Instance == htim4.Instance)
    {
        /* Toggle LED */
        HAL_GPIO_TogglePin(GPIOF, Motor4_PWM_Pin);
    }
		else if (htim->Instance == htim5.Instance)
    {
        /* Toggle LED */
        HAL_GPIO_TogglePin(GPIOF, Motor5_PWM_Pin);
    }
		else if (htim->Instance == htim6.Instance)
    {
        /* Toggle LED */
        HAL_GPIO_TogglePin(GPIOF, Motor6_PWM_Pin);
    }
		else if (htim->Instance == htim7.Instance)
    {
        /* Toggle LED */
        HAL_GPIO_TogglePin(GPIOF, Motor7_PWM_Pin);
    }
		else if (htim->Instance == htim8.Instance)
    {
        /* Toggle LED */
        HAL_GPIO_TogglePin(GPIOF, Motor8_PWM_Pin);
    }
}
/* USER CODE END 4 */

void Error_Handler(void)
{
  while(1)
  {
  }
}

/************************ (C) COPYRIGHT STMicroelectronics *****END OF FILE****/
